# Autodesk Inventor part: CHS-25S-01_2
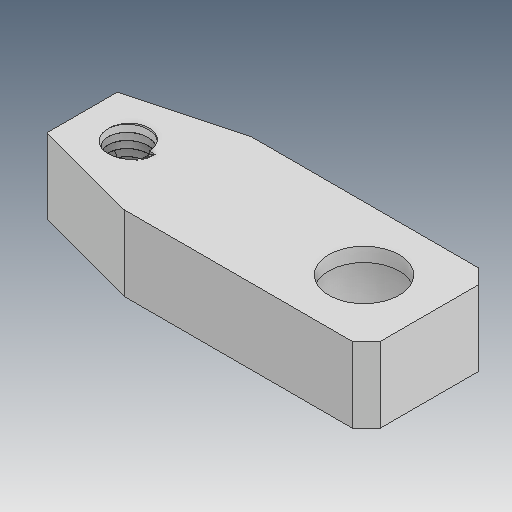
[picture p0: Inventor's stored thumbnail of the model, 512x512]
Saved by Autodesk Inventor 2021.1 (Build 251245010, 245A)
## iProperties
Created: 2019-05
Part Number: CHS-25S-01_2
Material: Ogólny
Document SubType Name: Modeling
Designer: user
Density: 1 g/cm^3
Appearance: Domyślna
Author: user
Revision Number: ÈÎºÎ
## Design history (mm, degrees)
feature "ÊäÈë1"
node "Bryła1"
